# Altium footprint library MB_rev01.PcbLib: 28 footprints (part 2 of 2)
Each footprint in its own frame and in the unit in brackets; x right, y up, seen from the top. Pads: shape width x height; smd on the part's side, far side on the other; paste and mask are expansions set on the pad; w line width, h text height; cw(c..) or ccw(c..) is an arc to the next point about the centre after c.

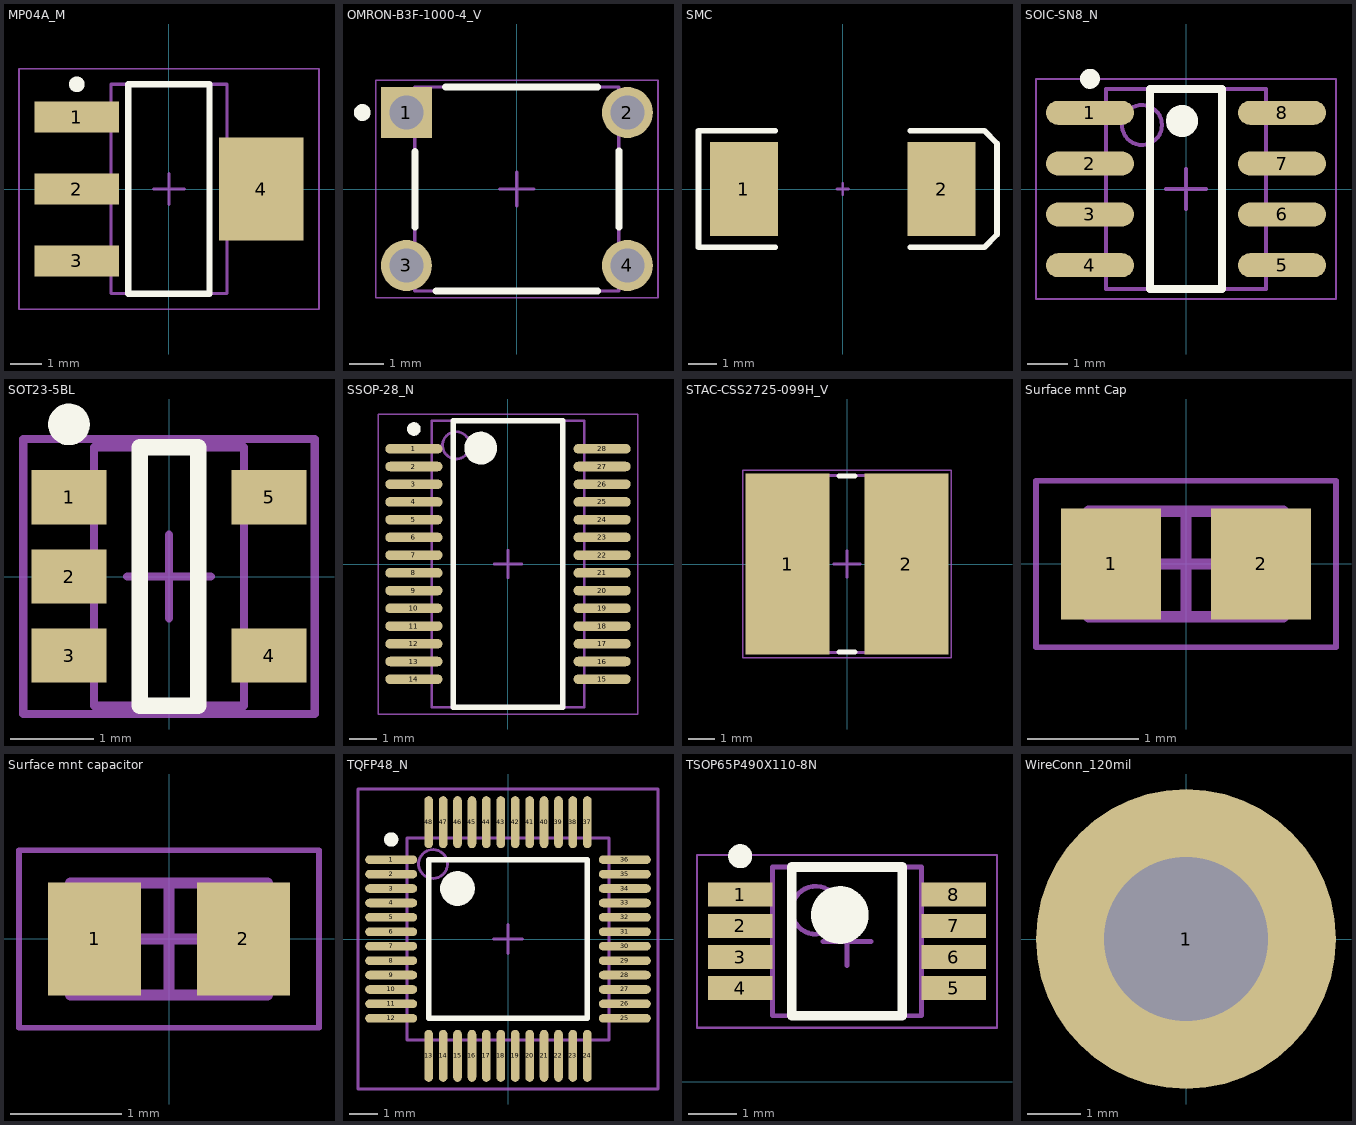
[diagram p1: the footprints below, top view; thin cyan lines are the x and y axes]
## MP04A_M [mm]
pads (4):
  rect 2.7x1 smd: 1(-2.95,2.3) 2(-2.95,0) 3(-2.95,-2.3)
  rect 2.7x3.3 smd: 4(2.95,0)
Top Overlay:
  circle w0.25: c-2.95,3.35 r0.125
  lines w0.2: -1.3,-3.35 1.3,-3.35 1.3,3.35 -1.3,3.35 -1.3,-3.35
Mechanical 13:
  lines w0.1: -1.855,-3.35 1.855,-3.35 1.855,3.35 -1.855,3.35 -1.855,-3.35
Mechanical 15:
  lines w0.05: -4.8,-3.85 4.8,-3.85 4.8,3.85 -4.8,3.85 -4.8,-3.85
  lines w0.1: -0.5,0 0.5,0 ; 0,-0.5 0,0.5
3D body: height 1.8, standoff 0.03, extent -1.855,-3.35 1.855,3.35

## OMRON-B3F-1000-4_V [mm]
pads (4):
  rect 1.5x1.5 hole 1 paste+0: 1(-3.25,2.25)
  round 1.5 hole 1 paste+0: 2(3.25,2.25) 3(-3.25,-2.25) 4(3.25,-2.25)
Top Overlay:
  circle w0.25: c-4.55,2.25 r0.125
  lines w0.2: -3,-1.127 -3,1.1 ; -2.378,-3 2.378,-3 ; -2.1,3 2.378,3 ; 3,-1.127 3,1.127
Mechanical 13:
  lines w0.1: -3,-3 -3,3 3,3 3,-3 -3,-3
Mechanical 15:
  lines w0.05: -4.15,-3.2 -4.15,3.2 4.15,3.2 4.15,-3.2 -4.15,-3.2
  lines w0.1: -0.5,0 0.5,0 ; 0,-0.5 0,0.5
3D body: height 4.5, standoff 0, extent -3,-3 3,3

## SMC [mm]
pads (2):
  rect 2.4x3.3 smd: 1(-3.475,0) 2(3.475,0)
Top Overlay:
  lines w0.2: -2.375,-2.05 -5.075,-2.05 -5.075,2.05 -2.375,2.05 ; 2.375,-2.05 4.975,-2.05 5.425,-1.6 5.425,1.6 4.975,2.055 ; 2.375,2.05 4.975,2.05
Mechanical 1:
  lines w0.1: -0.2,0 0.2,0 ; 0,-0.2 0,0.2

## SOIC-SN8_N [mm]
pads (8):
  oval 2.2x0.6 smd: 1(-2.4,1.905) 2(-2.4,0.635) 3(-2.4,-0.635) 4(-2.4,-1.905) 5(2.4,-1.905) 6(2.4,-0.635) 7(2.4,0.635) 8(2.4,1.905)
Top Overlay:
  circle w0.4: c-0.1,1.7 r0.2
  circle w0.25: c-2.4,2.755 r0.125
  lines w0.2: -0.9,-2.5 0.9,-2.5 0.9,2.5 -0.9,2.5 -0.9,-2.5
Mechanical 13:
  circle w0.1: c-1.1,1.6 r0.5
  lines w0.1: -2,-2.5 2,-2.5 2,2.5 -2,2.5 -2,-2.5
Mechanical 15:
  lines w0.05: -3.75,-2.75 3.75,-2.75 3.75,2.75 -3.75,2.75 -3.75,-2.75
  lines w0.1: -0.5,0 0.5,0 ; 0,-0.5 0,0.5
3D body: height 1.75, standoff 0.1, extent -2,-2.5 2,2.5

## SOT23-5BL [mm]
pads (5):
  rect 0.9x0.65 smd: 1(-1.2,0.95) 2(-1.2,0) 3(-1.2,-0.95) 4(1.2,-0.95) 5(1.2,0.95)
Top Overlay:
  circle w0.25: c-1.2,1.825 r0.125
  lines w0.2: -0.35,-1.55 0.35,-1.55 0.35,1.55 -0.35,1.55 -0.35,-1.55
Mechanical 13:
  lines w0.1: -0.9,-1.55 -0.9,1.55 0.9,1.55 0.9,-1.55 -0.9,-1.55
Mechanical 15:
  lines w0.1: -0.5,0 0.5,0 ; 0,-0.5 0,0.5 ; -1.75,-1.65 -1.75,1.65 1.75,1.65 1.75,-1.65 -1.75,-1.65
3D body: height 1.19, standoff 0, extent -0.9,-1.55 0.9,1.55

## SSOP-28_N [mm]
pads (28):
  oval 2.1x0.35 smd: 1(-3.45,4.225) 2(-3.45,3.575) 3(-3.45,2.925) 4(-3.45,2.275) 5(-3.45,1.625) 6(-3.45,0.975) 7(-3.45,0.325) 8(-3.45,-0.325) 9(-3.45,-0.975) 10(-3.45,-1.625) 11(-3.45,-2.275) 12(-3.45,-2.925) 13(-3.45,-3.575) 14(-3.45,-4.225) 15(3.45,-4.225) 16(3.45,-3.575) 17(3.45,-2.925) 18(3.45,-2.275) 19(3.45,-1.625) 20(3.45,-0.975) 21(3.45,-0.325) 22(3.45,0.325) 23(3.45,0.975) 24(3.45,1.625) 25(3.45,2.275) 26(3.45,2.925) 27(3.45,3.575) 28(3.45,4.225)
Top Overlay:
  circle w0.25: c-3.45,4.95 r0.125
  circle w0.6: c-1,4.25 r0.3
  lines w0.2: -2,-5.25 -2,5.25 2,5.25 2,-5.25 -2,-5.25
Mechanical 13:
  circle w0.1: c-1.9,4.35 r0.5
  lines w0.1: -2.8,-5.25 -2.8,5.25 2.8,5.25 2.8,-5.25 -2.8,-5.25
Mechanical 15:
  lines w0.05: -4.75,-5.5 -4.75,5.5 4.75,5.5 4.75,-5.5 -4.75,-5.5
  lines w0.1: -0.5,0 0.5,0 ; 0,-0.5 0,0.5
3D body: height 2, standoff 0.05, extent -2.8,-5.25 2.8,5.25

## STAC-CSS2725-099H_V [mm]
pads (2):
  rect 3.18x6.86 smd: 1(-2.25,0) 2(2.25,0)
Top Overlay:
  lines w0.2: -0.3,-3.33 0.3,-3.33 ; -0.3,3.33 0.3,3.33
Mechanical 13:
  lines w0.1: -3.53,-3.35 3.53,-3.35 3.53,3.35 -3.53,3.35 -3.53,-3.35
Mechanical 15:
  lines w0.05: -3.95,-3.55 3.95,-3.55 3.95,3.55 -3.95,3.55 -3.95,-3.55
  lines w0.1: -0.5,0 0.5,0 ; 0,-0.5 0,0.5
3D body "RESC6865X12L.step": height 1.24, standoff 0, extent -3.53,-3.35 3.53,3.35

## Surface mnt Cap [mm]
pads (2):
  rect 0.9x1 smd: 1(-0.675,0) 2(0.675,0)
Mechanical 13:
  lines w0.1: -0.875,-0.475 -0.875,0.475 0.875,0.475 0.875,-0.475 -0.875,-0.475
Mechanical 15:
  lines w0.05: -1.35,-0.75 -1.35,0.75 1.35,0.75 1.35,-0.75 -1.35,-0.75
  lines w0.1: -0.475,0 0.475,0 ; 0,-0.475 0,0.475
3D body: height 0.87, standoff 0, extent -0.525,-0.475 0.525,0.475
3D body: height 0.87, standoff 0, extent -0.875,-0.475 -0.525,0.475
3D body: height 0.87, standoff 0, extent 0.525,-0.475 0.875,0.475

## Surface mnt capacitor [mm]
pads (2):
  rect 0.84x1.02 smd: 1(-0.67,0) 2(0.67,0)
Mechanical 13:
  lines w0.1: -0.885,-0.505 -0.885,0.505 0.885,0.505 0.885,-0.505 -0.885,-0.505
Mechanical 15:
  lines w0.05: -1.35,-0.8 -1.35,0.8 1.35,0.8 1.35,-0.8 -1.35,-0.8
  lines w0.1: -0.5,0 0.5,0 ; 0,-0.5 0,0.5
3D body: height 0.91, standoff 0, extent -0.635,-0.505 0.635,0.505
3D body: height 0.91, standoff 0, extent -0.885,-0.505 -0.635,0.505
3D body: height 0.91, standoff 0, extent 0.635,-0.505 0.885,0.505

## TQFP48_N [mm]
pads (48):
  oval 1.8x0.3 smd: 1(-4.05,2.75) 2(-4.05,2.25) 3(-4.05,1.75) 4(-4.05,1.25) 5(-4.05,0.75) 6(-4.05,0.25) 7(-4.05,-0.25) 8(-4.05,-0.75) 9(-4.05,-1.25) 10(-4.05,-1.75) 11(-4.05,-2.25) 12(-4.05,-2.75) 25(4.05,-2.75) 26(4.05,-2.25) 27(4.05,-1.75) 28(4.05,-1.25) 29(4.05,-0.75) 30(4.05,-0.25) 31(4.05,0.25) 32(4.05,0.75) 33(4.05,1.25) 34(4.05,1.75) 35(4.05,2.25) 36(4.05,2.75)
  oval 0.3x1.8 smd: 13(-2.75,-4.05) 14(-2.25,-4.05) 15(-1.75,-4.05) 16(-1.25,-4.05) 17(-0.75,-4.05) 18(-0.25,-4.05) 19(0.25,-4.05) 20(0.75,-4.05) 21(1.25,-4.05) 22(1.75,-4.05) 23(2.25,-4.05) 24(2.75,-4.05) 37(2.75,4.05) 38(2.25,4.05) 39(1.75,4.05) 40(1.25,4.05) 41(0.75,4.05) 42(0.25,4.05) 43(-0.25,4.05) 44(-0.75,4.05) 45(-1.25,4.05) 46(-1.75,4.05) 47(-2.25,4.05) 48(-2.75,4.05)
Top Overlay:
  circle w0.25: c-4.05,3.45 r0.125
  circle w0.6: c-1.75,1.75 r0.3
  lines w0.2: -2.75,-2.75 -2.75,2.75 2.75,2.75 2.75,-2.75 -2.75,-2.75
Mechanical 13:
  circle w0.1: c-2.6,2.6 r0.5
  lines w0.1: -3.5,-3.5 -3.5,3.5 3.5,3.5 3.5,-3.5 -3.5,-3.5
Mechanical 15:
  lines w0.1: -0.5,0 0.5,0 ; 0,-0.5 0,0.5 ; -5.2,-5.2 -5.2,5.2 5.2,5.2 5.2,-5.2 -5.2,-5.2
3D body: height 1.2, standoff 0, extent -3.5,-3.5 3.5,3.5

## TSOP65P490X110-8N [mm]
pads (8):
  rect 1.35x0.5 smd: 1(-8.9,3.9) 2(-8.9,3.25) 3(-8.9,2.6) 4(-8.9,1.95) 5(-4.45,1.95) 6(-4.45,2.6) 7(-4.45,3.25) 8(-4.45,3.9)
Top Overlay:
  circle w0.25: c-8.9,4.7 r0.125
  circle w0.6: c-6.825,3.475 r0.3
  lines w0.2: -7.825,1.375 -7.825,4.475 -5.525,4.475 -5.525,1.375 -7.825,1.375
Mechanical 13:
  circle w0.1: c-7.325,3.575 r0.5
  lines w0.1: -8.225,1.375 -8.225,4.475 -5.125,4.475 -5.125,1.375 -8.225,1.375
Mechanical 15:
  lines w0.05: -9.8,1.125 -9.8,4.725 -3.55,4.725 -3.55,1.125 -9.8,1.125
  lines w0.1: -7.175,2.925 -6.175,2.925 ; -6.675,2.425 -6.675,3.425
3D body "TSOP65P490X110-8N.step": height 1.1, standoff 0, extent -9.127,1.375 -4.222,4.475

## WireConn_120mil [mil]
pads (1):
  round 220 hole 120: 1(0,0)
